VERSION 5.7 ;
  DIVIDERCHAR "/" ;
  BUSBITCHARS "[]" ;
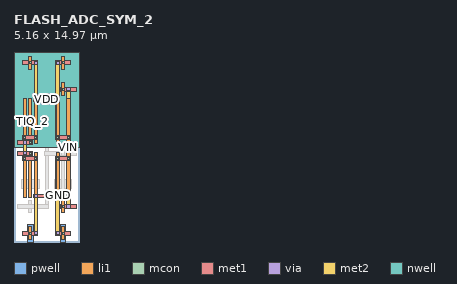
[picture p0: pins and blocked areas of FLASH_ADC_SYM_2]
MACRO FLASH_ADC_SYM_2
  CLASS BLOCK ;
  FOREIGN FLASH_ADC_SYM_2 ;
  ORIGIN 0.000 0.000 ;
  SIZE 5.160 BY 14.970 ;
  PIN GND
    ANTENNADIFFAREA 0.826000 ;
    PORT
      LAYER pwell ;
        RECT 1.075 0.000 1.505 1.380 ;
        RECT 3.655 0.000 4.085 1.380 ;
      LAYER li1 ;
        RECT 0.735 3.545 0.985 7.075 ;
        RECT 1.595 3.545 1.845 7.075 ;
        RECT 3.315 3.545 3.565 7.075 ;
        RECT 4.175 3.545 4.425 7.075 ;
        RECT 1.165 0.185 1.415 1.195 ;
        RECT 3.745 0.185 3.995 1.195 ;
      LAYER mcon ;
        RECT 0.775 6.485 0.945 6.655 ;
        RECT 1.635 6.485 1.805 6.655 ;
        RECT 3.355 6.485 3.525 6.655 ;
        RECT 4.215 6.485 4.385 6.655 ;
        RECT 1.205 0.605 1.375 0.775 ;
        RECT 3.785 0.605 3.955 0.775 ;
      LAYER met1 ;
        RECT 0.690 6.430 1.890 6.710 ;
        RECT 3.270 6.430 4.470 6.710 ;
        RECT 1.560 3.490 3.600 3.770 ;
        RECT 0.690 0.550 1.890 0.830 ;
        RECT 3.270 0.550 4.470 0.830 ;
      LAYER via ;
        RECT 1.590 6.440 1.850 6.700 ;
        RECT 3.310 6.440 3.570 6.700 ;
        RECT 1.590 3.500 1.850 3.760 ;
        RECT 3.310 3.500 3.570 3.760 ;
        RECT 1.590 0.560 1.850 0.820 ;
        RECT 3.310 0.560 3.570 0.820 ;
      LAYER met2 ;
        RECT 1.580 0.530 1.860 6.730 ;
        RECT 3.300 0.530 3.580 6.730 ;
    END
  END GND
  PIN VDD
    ANTENNADIFFAREA 1.716400 ;
    PORT
      LAYER nwell ;
        RECT 0.000 7.410 5.160 14.970 ;
      LAYER li1 ;
        RECT 1.165 13.625 1.415 14.635 ;
        RECT 3.745 13.625 3.995 14.635 ;
        RECT 0.735 7.745 0.985 11.275 ;
        RECT 1.595 7.745 1.845 11.275 ;
        RECT 3.315 7.745 3.565 11.275 ;
        RECT 4.175 7.745 4.425 11.275 ;
      LAYER mcon ;
        RECT 1.205 14.045 1.375 14.215 ;
        RECT 3.785 14.045 3.955 14.215 ;
        RECT 0.775 8.165 0.945 8.335 ;
        RECT 1.635 8.165 1.805 8.335 ;
        RECT 3.355 8.165 3.525 8.335 ;
        RECT 4.215 8.165 4.385 8.335 ;
      LAYER met1 ;
        RECT 0.690 13.990 1.890 14.270 ;
        RECT 3.270 13.990 4.470 14.270 ;
        RECT 1.560 11.050 3.600 11.330 ;
        RECT 0.690 8.110 1.890 8.390 ;
        RECT 3.270 8.110 4.470 8.390 ;
      LAYER via ;
        RECT 1.590 14.000 1.850 14.260 ;
        RECT 3.310 14.000 3.570 14.260 ;
        RECT 1.590 11.060 1.850 11.320 ;
        RECT 3.310 11.060 3.570 11.320 ;
        RECT 1.590 8.120 1.850 8.380 ;
        RECT 3.310 8.120 3.570 8.380 ;
      LAYER met2 ;
        RECT 1.580 8.090 1.860 14.290 ;
        RECT 3.300 8.090 3.580 14.290 ;
    END
  END VDD
  PIN VIN
    ANTENNAGATEAREA 0.504000 ;
    PORT
      LAYER li1 ;
        RECT 3.745 11.525 3.995 12.535 ;
        RECT 3.745 2.285 3.995 3.295 ;
      LAYER mcon ;
        RECT 3.785 11.945 3.955 12.115 ;
        RECT 3.785 2.705 3.955 2.875 ;
      LAYER met1 ;
        RECT 3.700 11.890 4.900 12.170 ;
        RECT 3.700 2.650 4.900 2.930 ;
      LAYER via ;
        RECT 4.170 11.900 4.430 12.160 ;
        RECT 4.170 2.660 4.430 2.920 ;
      LAYER met2 ;
        RECT 4.160 2.630 4.440 12.190 ;
    END
  END VIN
  PIN TIQ_2
    ANTENNADIFFAREA 0.470400 ;
    PORT
      LAYER li1 ;
        RECT 1.165 7.745 1.415 11.275 ;
        RECT 1.165 3.545 1.415 7.075 ;
      LAYER mcon ;
        RECT 1.205 7.745 1.375 7.915 ;
        RECT 1.205 6.905 1.375 7.075 ;
      LAYER met1 ;
        RECT 0.260 7.690 1.460 7.970 ;
        RECT 0.260 6.850 1.460 7.130 ;
      LAYER via ;
        RECT 0.730 7.700 0.990 7.960 ;
        RECT 0.730 6.860 0.990 7.120 ;
      LAYER met2 ;
        RECT 0.720 6.830 1.000 7.990 ;
    END
  END TIQ_2
  OBS
      LAYER pwell ;
        RECT 0.605 4.235 1.975 4.915 ;
        RECT 3.185 4.235 4.555 4.915 ;
      LAYER li1 ;
        RECT 1.165 11.525 1.415 12.535 ;
        RECT 1.165 2.285 1.415 3.295 ;
        RECT 2.455 2.705 2.705 12.115 ;
        RECT 3.745 7.745 3.995 11.275 ;
        RECT 3.745 3.545 3.995 7.075 ;
      LAYER mcon ;
        RECT 1.205 11.945 1.375 12.115 ;
        RECT 2.495 11.945 2.665 12.115 ;
        RECT 3.785 7.745 3.955 7.915 ;
        RECT 2.495 6.905 2.665 7.075 ;
        RECT 1.205 2.705 1.375 2.875 ;
        RECT 3.785 6.905 3.955 7.075 ;
        RECT 2.495 2.705 2.665 2.875 ;
      LAYER met1 ;
        RECT 0.260 11.890 2.750 12.170 ;
        RECT 3.700 7.690 4.900 7.970 ;
        RECT 2.410 6.850 4.900 7.130 ;
        RECT 0.260 2.650 2.750 2.930 ;
      LAYER via ;
        RECT 3.740 7.700 4.000 7.960 ;
        RECT 3.740 6.860 4.000 7.120 ;
      LAYER met2 ;
        RECT 3.730 6.830 4.010 7.990 ;
  END
END FLASH_ADC_SYM_2
END LIBRARY

